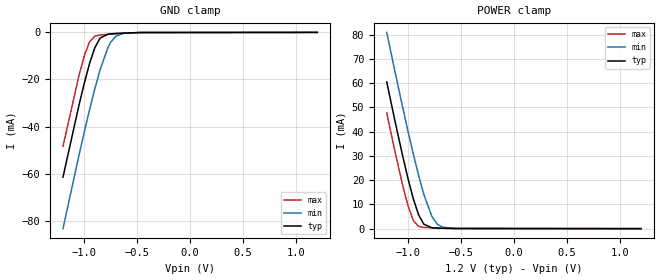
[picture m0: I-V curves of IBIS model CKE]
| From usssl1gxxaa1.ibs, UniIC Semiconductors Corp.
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|   Model CKE
[Model] CKE
Model_type Input
Vinl =  0.500V
Vinh =  0.700V
C_comp   1.051pF   1.012pF   1.102pF
[Model Spec]
Vinh   0.700V   0.670V   0.750V
Vinl   0.500V   0.470V   0.550V
[Temperature Range]   25.000   0.125k   -40.000
[Voltage Range]   1.200V   1.140V   1.300V
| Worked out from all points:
|   GND clamp passes 1 mA (typ) near -0.80 V on its own axis
|   POWER clamp passes 1 mA (typ) near -0.83 V on its own axis
[GND_clamp]
|Voltage   I(typ)   I(min)   I(max)
-1.2V     -61.45mA   -83.34mA   -48.37mA
-1.05V    -31.06mA   -52.35mA   -18.49mA
-1V       -21.76mA   -42.48mA   -10.1mA
-950mV    -13.34mA   -33mA      -4.038mA
-900mV    -6.537mA   -24.06mA   -1.604mA
-850mV    -2.438mA   -15.93mA   -1.096mA
-775mV    -749.3uA   -6.355mA   -818.5uA
-750mV    -614.8uA   -4.187mA   -740.6uA
-700mV    -456.4uA   -1.574mA   -591.9uA
-625mV    -287.5uA   -379.5uA   -387.7uA
-475mV    -54.84uA   -44.99uA   -81.36uA
1.2V      0A         0A         0A
[POWER_clamp]
|Voltage   I(typ)   I(min)   I(max)
-1.2V     60.47mA    80.89mA    47.72mA
-1.125V   44.92mA    65.28mA    32.29mA
-1.05V    30.03mA    50.09mA    17.91mA
-1V       20.75mA    40.29mA    9.545mA
-950mV    12.4mA     30.89mA    3.43mA
-900mV    5.743mA    22.06mA    945.4uA
-850mV    1.85mA     14.13mA    493.1uA
-775mV    370.8uA    5.133mA    339.4uA
-725mV    225.4uA    1.917mA    267.9uA
-675mV    162.2uA    621.7uA    203.8uA
-550mV    61.33uA    70.49uA    76.59uA
1.2V      0A         0A         0A
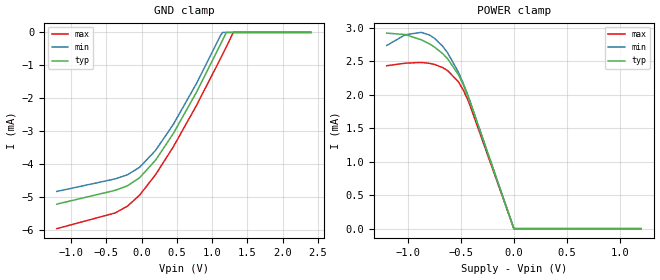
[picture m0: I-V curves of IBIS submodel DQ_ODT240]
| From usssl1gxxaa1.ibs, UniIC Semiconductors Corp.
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|   Submodel DQ_ODT240
[Submodel] DQ_ODT240
Submodel_type Dynamic_clamp
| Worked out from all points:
|   POWER clamp passes 1 mA (typ) near -0.22 V on its own axis
[GND_clamp]
|Voltage   I(typ)   I(min)   I(max)
-1.2V     -5.216mA   -4.83mA    -5.96mA
-375mV    -4.797mA   -4.45mA    -5.484mA
-200mV    -4.66mA    -4.325mA   -5.279mA
-25mV     -4.411mA   -4.093mA   -4.936mA
200mV     -3.875mA   -3.58mA    -4.318mA
450mV     -3.072mA   -2.795mA   -3.476mA
775mV     -1.829mA   -1.563mA   -2.231mA
1.125V    -335.4uA   -67.06uA   -766.2uA
1.15V     -224.1uA   0A         -657.9uA
1.2V      0A         0A         -440.2uA
1.3V      0A         0A         0A
2.4V      0A         0A         0A
[POWER_clamp]
|Voltage   I(typ)   I(min)   I(max)
-1.2V     2.92mA     2.736mA    2.433mA
-1.025V   2.898mA    2.896mA    2.471mA
-875mV    2.821mA    2.931mA    2.482mA
-800mV    2.762mA    2.894mA    2.47mA
-750mV    2.713mA    2.844mA    2.453mA
-675mV    2.618mA    2.729mA    2.407mA
-625mV    2.536mA    2.624mA    2.36mA
-525mV    2.304mA    2.342mA    2.197mA
-475mV    2.14mA     2.16mA     2.063mA
-425mV    1.942mA    1.954mA    1.887mA
0V        -796.2fA   -3.708pA   1.564pA
1.2V      0A         0A         0A
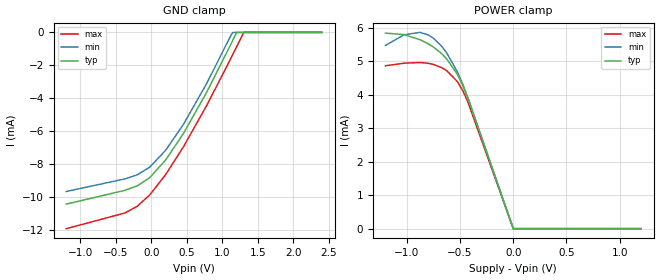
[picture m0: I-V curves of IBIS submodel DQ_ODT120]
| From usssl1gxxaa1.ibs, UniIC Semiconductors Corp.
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|   Submodel DQ_ODT120
[Submodel] DQ_ODT120
Submodel_type Dynamic_clamp
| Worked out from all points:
|   POWER clamp passes 1 mA (typ) near -0.11 V on its own axis
[GND_clamp]
|Voltage   I(typ)   I(min)   I(max)
-1.2V     -10.43mA   -9.66mA    -11.92mA
-375mV    -9.594mA   -8.9mA     -10.97mA
-200mV    -9.321mA   -8.65mA    -10.56mA
-25mV     -8.823mA   -8.187mA   -9.872mA
200mV     -7.75mA    -7.159mA   -8.636mA
450mV     -6.144mA   -5.589mA   -6.953mA
775mV     -3.659mA   -3.126mA   -4.462mA
1.125V    -670.8uA   -134.1uA   -1.532mA
1.15V     -448.2uA   0A         -1.316mA
1.2V      0A         0A         -880.3uA
1.3V      0A         0A         0A
2.4V      0A         0A         0A
[POWER_clamp]
|Voltage   I(typ)   I(min)   I(max)
-1.2V     5.84mA     5.473mA    4.866mA
-1.025V   5.796mA    5.792mA    4.942mA
-875mV    5.643mA    5.862mA    4.963mA
-800mV    5.524mA    5.789mA    4.94mA
-750mV    5.425mA    5.689mA    4.905mA
-675mV    5.235mA    5.458mA    4.815mA
-625mV    5.072mA    5.249mA    4.719mA
-525mV    4.608mA    4.685mA    4.394mA
-475mV    4.28mA     4.321mA    4.127mA
-425mV    3.884mA    3.907mA    3.774mA
0V        -1.592pA   -7.417pA   3.128pA
1.2V      0A         0A         0A
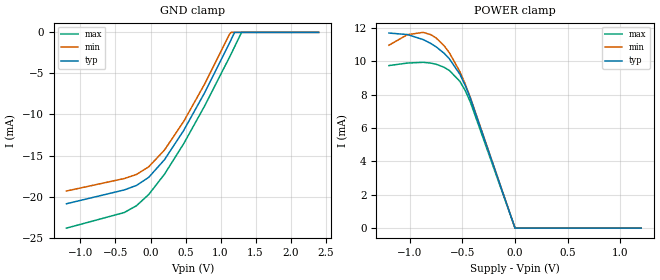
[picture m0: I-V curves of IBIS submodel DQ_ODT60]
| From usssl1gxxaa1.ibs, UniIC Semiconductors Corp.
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|   Submodel DQ_ODT60
[Submodel] DQ_ODT60
Submodel_type Dynamic_clamp
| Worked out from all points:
|   POWER clamp passes 1 mA (typ) near -0.06 V on its own axis
[GND_clamp]
|Voltage   I(typ)   I(min)   I(max)
-1.2V     -20.87mA   -19.32mA   -23.84mA
-375mV    -19.19mA   -17.8mA    -21.94mA
-200mV    -18.64mA   -17.3mA    -21.11mA
-25mV     -17.65mA   -16.37mA   -19.74mA
200mV     -15.5mA    -14.32mA   -17.27mA
475mV     -11.93mA   -10.83mA   -13.54mA
775mV     -7.318mA   -6.253mA   -8.923mA
1.125V    -1.342mA   -268.3uA   -3.065mA
1.15V     -896.5uA   0A         -2.632mA
1.2V      0A         0A         -1.761mA
1.3V      0A         0A         0A
2.4V      0A         0A         0A
[POWER_clamp]
|Voltage   I(typ)   I(min)   I(max)
-1.2V     11.68mA    10.95mA    9.732mA
-1.025V   11.59mA    11.58mA    9.883mA
-875mV    11.29mA    11.72mA    9.927mA
-800mV    11.05mA    11.58mA    9.88mA
-750mV    10.85mA    11.38mA    9.811mA
-675mV    10.47mA    10.92mA    9.63mA
-625mV    10.14mA    10.5mA     9.439mA
-525mV    9.215mA    9.369mA    8.788mA
-475mV    8.559mA    8.642mA    8.254mA
-425mV    7.768mA    7.815mA    7.547mA
0V        -3.185pA   -14.83pA   6.255pA
1.2V      0A         0A         0A
